VERSION 5.8 ;
UNITS
  DATABASE MICRONS 1000 ;
END UNITS

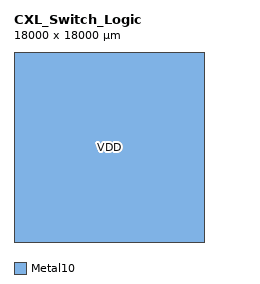
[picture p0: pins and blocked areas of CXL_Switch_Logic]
MACRO CXL_Switch_Logic
  CLASS BLOCK ;
  SIZE 18000 BY 18000 ;
  ORIGIN 0 0 ;
  SYMMETRY X Y ;
  PIN VDD
    DIRECTION INOUT ;
    USE POWER ;
    PORT
      LAYER Metal10 ;
      RECT 0 0 18000 18000 ;
    END
  END VDD
END CXL_Switch_Logic

MACRO SRAM_Search_Die
  CLASS BLOCK ;
  SIZE 15000 BY 15000 ;
  ORIGIN 0 0 ;
  SYMMETRY X Y ;
END SRAM_Search_Die

END LIBRARY
